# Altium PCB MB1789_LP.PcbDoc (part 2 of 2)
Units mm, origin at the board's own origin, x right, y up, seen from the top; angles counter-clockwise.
Board outline 60 x 34 mm, 4 copper layers (Top Layer, Mid-Layer 1, Mid-Layer 2, Bottom Layer), stack 1.07 mm thick; 67 components, 56 nets, 214 pads, 993 vias.

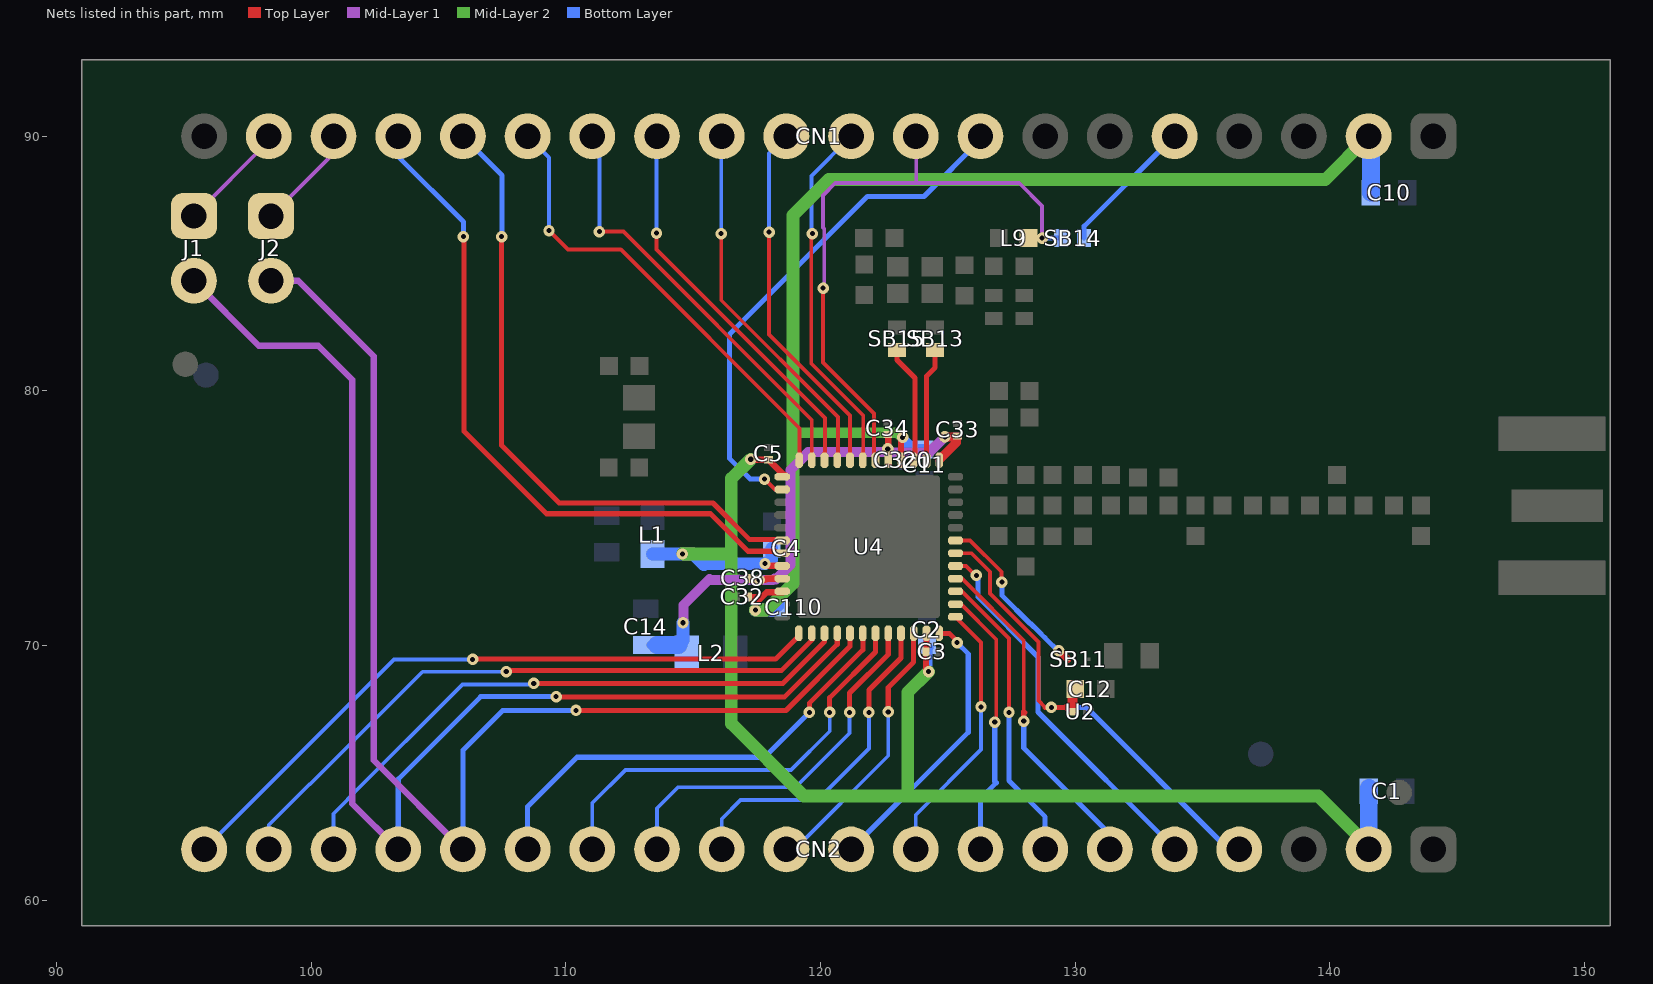
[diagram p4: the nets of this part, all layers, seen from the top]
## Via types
v1: diameter 0.45, hole 0.2, Top Layer to Bottom Layer, 992 vias
v2: diameter 0.45, hole 0.2, Top Layer to Bottom Layer, tented bottom, 1 vias

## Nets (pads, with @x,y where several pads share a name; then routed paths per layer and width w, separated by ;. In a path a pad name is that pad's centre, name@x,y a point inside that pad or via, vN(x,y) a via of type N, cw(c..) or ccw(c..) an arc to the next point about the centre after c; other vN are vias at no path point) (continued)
NetSB11_2: SB11.2 U4.19 | length 7
  Top Layer w0.15: U4.19@125.296,74.132 125.871,74.132 127.1,72.903 127.1,72.48 v1@127.12,72.46
  Top Layer w0.2: v1(129.36,69.8) v1@129.369,69.8
  Top Layer w0.3: v1@129.369,69.8 SB11.2@129.7,69.469
  Bottom Layer w0.2: v1(127.12,72.5) 127.12,71.98 128.224,70.875 128.245,70.875 128.555,70.565 ; 128.555,70.564 128.804,70.315 ; 128.805,70.315 129.36,69.76 v1(129.36,69.8)
NetSB13_1: SB13.1 U4.26 | length 4.5
  Top Layer w0.2: U4.26@124.158,77.282 124.158,80.578 124.5,80.92 SB13.1@124.5,81.6
NetSB15_1: SB15.1 U4.27 | length 4.6
  Top Layer w0.2: SB15.1@123,81.6 123,81.22 123.71,80.51 123.71,77.334 U4.27@123.658,77.282
NRST: C12.1 CN2.4 U2.1 U4.18 | length 19.5
  Top Layer w0.15: U4.18@125.296,73.632 125.926,73.632 126.655,72.903 126.655,72.05 128.555,70.15 128.555,67.845 128.82,67.58
  Top Layer w0.2: 128.82,67.58 v1(129.06,67.58) 129.588,67.58 129.608,67.6 129.648,67.56 129.688,67.6 U2.1@129.788,67.5 ; C12.1@129.888,68.188 C12.1@130,68.3
  Top Layer w0.4: U2.1@129.888,67.5 C12.1@129.888,68.188
  Bottom Layer w0.2: v1(129.06,67.58) 130.44,67.58 136.02,62 CN2.4@136.44,62
PA0: CN2.14 U4.7 | length 16.9
  Top Layer w0.2: v1(120.36,67.38) 120.36,67.957 122.158,69.755 U4.7@122.158,70.485
  Bottom Layer w0.15: CN2.14@111.04,62 111.04,63.82 112.34,65.12 118.84,65.12 120.36,66.64 v1(120.36,67.38)
PA1: CN2.13 U4.8 | length 15
  Top Layer w0.2: v1(121.14,67.38) 121.14,68.14 122.658,69.658 U4.8@122.658,70.485
  Bottom Layer w0.15: CN2.13@113.58,62 113.58,63.62 114.4,64.44 119.02,64.44 121.14,66.56 v1(121.14,67.38)
PA2: CN2.12 U4.9 | length 13.2
  Top Layer w0.2: v1(121.9,67.38) 121.9,68.26 123.158,69.518 U4.9@123.158,70.485
  Bottom Layer w0.15: CN2.12@116.12,62 116.12,63.2 116.86,63.94 119.88,63.94 121.9,65.96 v1(121.9,67.38)
PA3: CN2.11 U4.10 | length 10.8
  Top Layer w0.2: v1@122.6,67.36 122.66,67.42 122.66,68.36 123.658,69.358 U4.10@123.658,70.485
  Bottom Layer w0.15: CN2.11@118.66,62 118.98,62 122.66,65.68 v1(122.66,67.4)
PA4: CN2.10 U4.12 | length 11.1
  Top Layer w0.2: U4.12@124.658,70.485 125.055,70.485 125.4,70.14 v1@125.4,70.1
  Bottom Layer w0.2: CN2.10@121.2,62 125.8,66.6 125.8,69.68 v1(125.36,70.12)
PA5: CN2.9 U4.13 | length 10.6
  Top Layer w0.15: U4.13@125.296,71.132 126.3,70.128 v1(126.3,67.6)
  Bottom Layer w0.15: CN2.9@123.74,62 123.74,63.36 126.3,65.92 v1(126.3,67.6)
PA6: CN2.8 U4.14 | length 10.7
  Top Layer w0.15: U4.14@125.296,71.632 125.51,71.632 126.9,70.242 126.9,67.06 v1(126.84,67)
  Bottom Layer w0.2: CN2.8@126.28,62 126.28,64 126.9,64.62 126.84,64.68 v1(126.84,67)
PA7: CN2.7 U4.15 | length 11.7
  Top Layer w0.15: U4.15@125.296,72.132 125.548,72.132 127.4,70.28 v1(127.4,67.38)
  Bottom Layer w0.2: v1(127.4,67.38) 127.4,64.7 128.82,63.28 CN2.7@128.82,62
PA8: CN2.6 U4.16 | length 13.3
  Top Layer w0.15: U4.16@125.296,72.632 125.554,72.632 127.98,70.205 127.98,67.42
  Top Layer w0.2: v1(127.98,67.04) 127.98,67.34 128.02,67.38 127.98,67.42
  Bottom Layer w0.2: v1(127.98,67.04) 127.98,65.98 131.36,62.6 CN2.6@131.36,62
PA9: CN2.5 U4.17 | length 15
  Top Layer w0.15: U4.17@125.296,73.132 125.709,73.132 126.141,72.7 126.161,72.72 v1(126.121,72.76)
  Bottom Layer w0.2: v1@126.18,72.7 126.18,71.92 128.54,69.56 128.54,67.4 CN2.5@133.95,61.99
PA10: CN1.12 U4.33 | length 14.9
  Top Layer w0.15: v1@116.1,86.22 v1(116.1,86.18) 116.1,83.56 120.68,78.98 U4.33@120.68,77.26 ; U4.33@120.658,77.282 U4.33@120.658,77.541
  Bottom Layer w0.15: v1(116.1,86.18) 116.1,89.98 CN1.12@116.12,90
PA11: CN1.13 U4.34 | length 15.9
  Top Layer w0.15: v1@113.56,86.26 v1(113.56,86.2) 113.56,85.56 120.18,78.94 U4.34@120.18,77.3 ; U4.34@120.14,77.2 U4.34@120.14,77.54
  Bottom Layer w0.15: v1(113.56,86.2) 113.56,89.98 CN1.13@113.58,90
PA12: CN1.14 U4.35 | length 16.8
  Top Layer w0.15: v1(111.32,86.26) 112.26,86.26 119.658,78.862 U4.35@119.658,77.282
  Bottom Layer w0.15: CN1.14@111.04,90 111.32,89.72 v1(111.32,86.26)
PA13: CN1.15 U4.36 | length 18.3
  Top Layer w0.15: v1(109.34,86.3) 110.08,85.56 112.16,85.56 119.18,78.54 U4.36@119.18,77.3
  Bottom Layer w0.15: CN1.15@108.5,90 109.34,89.16 v1(109.34,86.3)
PA14: CN1.16 U4.42 | length 25.4
  Top Layer w0.2: v1@107.48,86.04 107.48,77.86 109.74,75.6 115.78,75.6 117.218,74.162 U4.42@118.6,74.162
  Bottom Layer w0.2: CN1.16@105.96,90 107.5,88.46 107.5,86.08 v1(107.48,86.06)
PA15: CN1.17 U4.43 | length 27.2
  Top Layer w0.2: v1@106,86.06 106,78.42 109.24,75.18 115.68,75.18 117.15,73.71 118.21,73.71 118.28,73.64 118.578,73.64 U4.43@118.6,73.662
  Bottom Layer w0.2: CN1.17@103.42,90 103.42,89.2 105.98,86.64 v1(105.98,86.06)
PB0: CN1.9 L9.2 SB14.1 U4.30 | length 24.8
  Top Layer w0.15: v1(120.1,84.04) 120.08,84.04 120.1,84.02 120.1,81.12 122.1,79.12 122.1,77.34 U4.30@122.158,77.282
  Top Layer w0.2: L9.2@128.16,86 v1(128.7,86)
  Mid-Layer 1 w0.15: v1@120.1,84.08 120.145,84.125 120.145,86.373 120.1,86.418 120.1,87.68 120.58,88.16 127.8,88.16 128.7,87.26 v1(128.7,86) ; CN1.9@123.74,89.94 123.76,89.96 123.76,88.16
  Bottom Layer w0.2: v1(128.7,86) SB14.1@129.45,86
PB2: CN1.10 U4.31 | length 14.5
  Top Layer w0.15: v1(119.68,86.18) 119.635,86.135 119.635,81.085 121.68,79.04 U4.31@121.68,77.32 ; U4.31@121.658,77.282 U4.31@121.658,77.562
  Bottom Layer w0.15: v1(119.68,86.18) 119.64,86.22 119.64,88.44 CN1.10@121.2,90
PB3: CN2.20 U4.1 | length 26.9
  Top Layer w0.2: v1@106.36,69.48 118.24,69.48 119.151,70.391 U4.1@119.151,70.485
  Bottom Layer w0.15: CN2.20@95.8,62 103.26,69.46 v1(106.34,69.46)
PB4: CN2.19 U4.2 | length 25.5
  Top Layer w0.2: v1@107.66,69.02 118.46,69.02 119.658,70.218 U4.2@119.658,70.485
  Bottom Layer w0.15: CN2.19@98.34,62 98.34,62.96 99.94,64.56 99.96,64.56 104.38,68.98 v1(107.66,68.98)
PB5: CN2.18 U4.3 | length 23.8
  Top Layer w0.2: v1@108.78,68.52 118.52,68.52 120.158,70.158 U4.3@120.158,70.485
  Bottom Layer w0.15: CN2.18@100.88,62 100.88,63.4 101.44,63.96 101.44,63.98 105.94,68.48 108.7,68.48 v1(108.74,68.52)
PB6: CN2.17 J1.2 U4.4 | length 49.7
  Top Layer w0.2: v1@109.58,67.98 118.58,67.98 120.658,70.058 U4.4@120.658,70.485
  Mid-Layer 1 w0.25: J1.2@95.4,84.33 97.95,81.78 100.28,81.78 101.62,80.44 101.62,63.8 CN2.17@103.42,62
  Bottom Layer w0.2: CN2.17@103.42,62 103.42,64.76 106.66,68 v1(109.62,68)
PB7: CN2.16 J2.2 U4.5 | length 47.4
  Top Layer w0.2: v1(110.4,67.46) 118.64,67.46 121.158,69.978 U4.5@121.158,70.485
  Mid-Layer 1 w0.2: 102.46,67.48 102.48,67.46
  Mid-Layer 1 w0.25: J2.2@98.425,84.328 99.492,84.328 102.46,81.36 102.46,67.48 102.46,65.5 CN2.16@105.96,62
  Bottom Layer w0.2: CN2.16@105.96,62 105.96,65.9 107.52,67.46 v1(110.4,67.46)
PB8: CN2.15 U4.6 | length 18.7
  Top Layer w0.15: U4.6@121.618,70.445 U4.6@121.658,70.485 U4.6@121.658,70.235
  Top Layer w0.2: v1@119.56,67.34 v1(119.56,67.38) 119.56,67.74 121.66,69.84 U4.6@121.66,70.56
  Bottom Layer w0.2: CN2.15@108.5,62 108.5,63.68 110.44,65.62 117.8,65.62 v1(119.56,67.38)
PB12: CN1.11 U4.32 | length 14.3
  Top Layer w0.15: v1@117.98,86.26 117.98,82.22 121.158,79.042 U4.32@121.158,77.282
  Bottom Layer w0.15: v1(117.98,86.24) 117.98,89.32 CN1.11@118.66,90
PC13: CN1.8 U4.38 | length 20.5
  Top Layer w0.15: v1(117.8,76.54) 118.208,76.132 U4.38@118.498,76.132
  Bottom Layer w0.2: v1(117.8,76.54) 117.24,76.54 116.42,77.36 116.42,82.221 121.839,87.64 124.06,87.64 CN1.8@126.32,89.9
UART_RX: CN1.18 J2.1 | length 4.1
  Mid-Layer 1 w0.15: J2.1@98.425,86.868 100.88,89.323 CN1.18@100.88,90
UART_TX: CN1.19 J1.1 | length 4.3
  Mid-Layer 1 w0.15: J1.1@95.4,86.87 98.34,89.81 CN1.19@98.34,90
VDD: C1.2 C2.2 C3.2 C4.2 C5.2 CN2.2 L1.1 U4.11 U4.37 U4.44 | length 57.7
  Top Layer w0.25: v1(117.26,77.32) 117.28,77.3 C5.2@117.96,77.3 U4.37@118.598,76.662 ; v1(117.82,73.22) 117.908,73.132 U4.44@118.498,73.132 ; C3.2@124.14,69.76 124.14,69.08 v1(124.24,68.98) ; U4.11@124.158,70.485 C3.2@124.16,69.8
  Top Layer w0.3: U4.37@118.598,76.662 U4.37@118.6,76.662
  Mid-Layer 2 w0.5: v1@114.6,73.62 114.62,73.6 116.5,73.6 ; v1(117.26,77.32) 116.5,76.56 116.5,73.6 ; v1(124.24,68.98) 123.42,68.16 123.42,64.1 ; CN2.2@141.56,62.08 139.54,64.1 123.42,64.1 ; 116.5,73.6 116.5,66.94 119.34,64.1 123.42,64.1
  Bottom Layer w0.25: C2.2@124.18,70.02 C2.2@124.258,69.942
  Bottom Layer w0.3: v1(124.24,68.98) 124.24,69.84 124.26,69.86 124.24,69.88 124.28,69.92 C2.2@124.258,69.942
  Bottom Layer w0.5: L1.1@113.4,73.6 115,73.6 115.425,73.175 115.47,73.22 v1(117.82,73.22) 117.835,73.22 117.875,73.26 117.958,73.26 118.082,73.384 C4.2@118.082,73.82
  Bottom Layer w0.7: CN2.2@141.52,61.98 C1.2@141.52,64.42
  other v1: 114.58,73.6
VDD_TCXO_EXT: CN1.5 SB14.2 | length 5.1
  Bottom Layer w0.2: SB14.2@130.35,86 130.35,86.47 CN1.5@133.6,89.72
VDDPA: C14.1 C33.2 C34.2 C38.1 L2.1 U4.25 U4.29 U4.45 | length 22.8
  Top Layer w0.254: C38.1@117.26,72.62 117.3,72.58 v1(117.588,72.58) 117.82,72.58 117.872,72.632 U4.45@118.498,72.632 ; U4.29@122.658,77.282 C34.2@122.658,78.18
  Top Layer w0.3: U4.25@124.658,77.282 U4.25@124.718,77.342
  Top Layer w0.35: U4.25@124.718,77.342 124.718,77.358 125.34,77.98 C33.2@125.34,78.2 ; v1(124.88,78.2) C33.2@125.38,78.2
  Mid-Layer 1 w0.4: v1(114.6,70.9) 114.62,70.92 114.62,71.6 115.64,72.62 115.68,72.58 v1(117.588,72.58) 118.129,72.58 118.168,72.62 118.174,72.614 118.2,72.64 118.24,72.6 118.82,73.18 118.82,76.9 119.52,77.6 122.578,77.6 122.64,77.662 v1(122.64,77.726) 122.64,77.698 122.748,77.59 124.27,77.59 124.85,78.17 v1@124.91,78.17
  Bottom Layer w0.4: C14.1@113.363,70.026 C14.1@113.574,70.026 ; L2.1@114.423,70.026 L2.1@114.6,70.204 ; L2.1@114.6,70.071 v1(114.6,70.9)
  Bottom Layer w0.5: L2.1@114.6,70.204 v1(114.6,70.9)
  Bottom Layer w0.7: C14.1@113.574,70.026 L2.1@114.423,70.026
VDDRF: C10.1 C11.1 C32.2 C110.1 C320.2 CN1.2 U4.28 U4.46 | length 53
  Top Layer w0.2: v1(117.44,71.4) 117.44,71.66 ; U4.46@118.558,72.12 U4.46@118.6,72.162
  Top Layer w0.25: C32.2@117.24,71.92 117.26,71.9 117.68,71.9 ; U4.46@118.558,72.12 118.543,72.105 117.885,72.105 117.68,71.9 ; v1@123.12,78.18 123.14,78.16 123.158,78.178 U4.28@123.158,77.282 ; v1@123.16,78.18 v1(123.22,78.18) ; 117.68,71.9 117.44,71.66 117.68,71.9
  Mid-Layer 2 w0.4: 118.92,78.36 123.015,78.36 123.195,78.18 v1(123.22,78.18)
  Mid-Layer 2 w0.5: v1(117.44,71.4) 117.88,71.4 118.92,72.44 118.92,78.36 118.92,86.9 120.32,88.3 139.82,88.3 CN1.2@141.52,90
  Bottom Layer w0.25: C320.2@123.22,77.52 123.22,78.155 v1(123.22,78.18)
  Bottom Layer w0.4: v1@123.22,78.155 123.655,77.72 C11.1@124.1,77.72
  Bottom Layer w0.5: v1(117.44,71.4) 118.12,71.4 118.32,71.6 C110.1@118.342,71.6
  Bottom Layer w0.7: CN1.2@141.52,90 141.607,89.912 C10.1@141.607,87.78
pads on no net: CN1.3 CN1.7 CN2.3 Designator1.1 Designator2.1 Designator3.1 Designator4.1 U4.23
copper on no net: | length 2656.1
  Top Layer w0.025: 179.648,184.046 182.18,186.578 185.228,189.626 188.276,192.674 191.324,195.722 194.372,198.77 197.42,201.818 200.468,204.866 203.516,207.914 206.564,210.962 208.088,212.486 ; 179.648,185.57 180.656,186.578 183.704,189.626 186.752,192.674 189.8,195.722 192.848,198.77 195.896,201.818 198.944,204.866 201.992,207.914 205.04,210.962 208.088,214.01 ; 179.648,187.094 182.18,189.626 185.228,192.674 188.276,195.722 191.324,198.77 194.372,201.818 197.42,204.866 200.468,207.914 203.516,210.962 206.564,214.01 208.088,215.534 ; 179.648,188.618 180.656,189.626 183.704,192.674 186.752,195.722 189.8,198.77 192.848,201.818 195.896,204.866 198.944,207.914 201.992,210.962 205.04,214.01 208.088,217.058 ; 179.648,190.142 182.18,192.674 185.228,195.722 188.276,198.77 191.324,201.818 194.372,204.866 197.42,207.914 200.468,210.962 203.516,214.01 206.564,217.058 ; 179.648,191.666 180.656,192.674 183.704,195.722 186.752,198.77 189.8,201.818 192.848,204.866 195.896,207.914 198.944,210.962 201.992,214.01 205.04,217.058 ; 179.648,193.19 182.18,195.722 185.228,198.77 188.276,201.818 191.324,204.866 194.372,207.914 197.42,210.962 200.468,214.01 203.516,217.058 ; 179.648,194.714 180.656,195.722 183.704,198.77 186.752,201.818 189.8,204.866 192.848,207.914 195.896,210.962 198.944,214.01 201.992,217.058 ; 179.648,196.238 182.18,198.77 185.228,201.818 188.276,204.866 191.324,207.914 194.372,210.962 197.42,214.01 200.468,217.058 ; 179.648,197.762 180.656,198.77 183.704,201.818 186.752,204.866 189.8,207.914 192.848,210.962 195.896,214.01 198.944,217.058 ; 179.648,199.286 182.18,201.818 185.228,204.866 188.276,207.914 191.324,210.962 194.372,214.01 197.42,217.058 ; 179.648,200.81 180.656,201.818 183.704,204.866 186.752,207.914 189.8,210.962 192.848,214.01 195.896,217.058 ; 179.648,202.334 182.18,204.866 185.228,207.914 188.276,210.962 191.324,214.01 194.372,217.058 ; 179.648,203.858 180.656,204.866 183.704,207.914 186.752,210.962 189.8,214.01 192.848,217.058 ; 179.648,205.382 182.18,207.914 185.228,210.962 188.276,214.01 191.324,217.058 ; 179.648,206.906 180.656,207.914 183.704,210.962 186.752,214.01 189.8,217.058 ; 179.648,208.43 182.18,210.962 185.228,214.01 188.276,217.058 ; 179.648,209.954 180.656,210.962 183.704,214.01 186.752,217.058 ; 179.648,211.478 182.18,214.01 185.228,217.058 ; 179.648,213.002 180.656,214.01 183.704,217.058 ; 179.648,214.526 182.18,217.058 ; 179.648,216.05 180.656,217.058 ; 180.656,183.53 183.704,186.578 186.752,189.626 189.8,192.674 192.848,195.722 195.896,198.77 198.944,201.818 201.992,204.866 205.04,207.914 208.088,210.962 ; 182.18,183.53 185.228,186.578 188.276,189.626 191.324,192.674 194.372,195.722 197.42,198.77 200.468,201.818 203.516,204.866 206.564,207.914 208.088,209.438 ; 183.704,183.53 186.752,186.578 189.8,189.626 192.848,192.674 195.896,195.722 198.944,198.77 201.992,201.818 205.04,204.866 208.088,207.914 ; 185.228,183.53 188.276,186.578 191.324,189.626 194.372,192.674 197.42,195.722 200.468,198.77 203.516,201.818 206.564,204.866 208.088,206.39 ; 186.752,183.53 189.8,186.578 192.848,189.626 195.896,192.674 198.944,195.722 201.992,198.77 205.04,201.818 208.088,204.866 ; 188.276,183.53 191.324,186.578 194.372,189.626 197.42,192.674 200.468,195.722 203.516,198.77 206.564,201.818 208.088,203.342 ; 189.8,183.53 192.848,186.578 195.896,189.626 198.944,192.674 201.992,195.722 205.04,198.77 208.088,201.818 ; 191.324,183.53 194.372,186.578 197.42,189.626 200.468,192.674 203.516,195.722 206.564,198.77 208.088,200.294 ; 192.848,183.53 195.896,186.578 198.944,189.626 201.992,192.674 205.04,195.722 208.088,198.77 ; 194.372,183.53 197.42,186.578 200.468,189.626 203.516,192.674 206.564,195.722 208.088,197.246 ; 195.896,183.53 198.944,186.578 201.992,189.626 205.04,192.674 208.088,195.722 ; 197.42,183.53 200.468,186.578 203.516,189.626 206.564,192.674 208.088,194.198 ; 198.944,183.53 201.992,186.578 205.04,189.626 208.088,192.674 ; 200.468,183.53 203.516,186.578 206.564,189.626 208.088,191.15 ; 201.992,183.53 205.04,186.578 208.088,189.626 ; 203.516,183.53 206.564,186.578 208.088,188.102 ; 205.04,183.53 208.088,186.578 ; 206.564,183.53 208.088,185.054
  Top Layer w0.381: 91.532,186.578 101.944,186.578 125.56,186.578 148.667,186.578 165.173,186.578 179.648,186.578 208.088,186.578 ; 91.532,189.626 101.944,189.626 125.56,189.626 148.667,189.626 165.173,189.626 179.648,189.626 208.088,189.626 ; 91.532,192.674 101.944,192.674 125.56,192.674 148.667,192.674 165.173,192.674 179.648,192.674 208.088,192.674 ; 91.532,195.722 101.944,195.722 125.56,195.722 148.667,195.722 165.173,195.722 179.648,195.722 208.088,195.722 ; 91.532,198.77 101.944,198.77 125.56,198.77 148.667,198.77 165.173,198.77 179.648,198.77 208.088,198.77 ; 91.532,201.818 101.944,201.818 125.56,201.818 148.667,201.818 165.173,201.818 179.648,201.818 208.088,201.818 ; 91.532,204.866 101.944,204.866 125.56,204.866 148.667,204.866 165.173,204.866 179.648,204.866 208.088,204.866 ; 91.532,207.914 101.944,207.914 125.56,207.914 148.667,207.914 165.173,207.914 179.648,207.914 208.088,207.914 ; 91.532,210.962 101.944,210.962 125.56,210.962 148.667,210.962 165.173,210.962 179.648,210.962 208.088,210.962 ; 91.532,214.01 101.944,214.01 125.56,214.01 148.667,214.01 165.173,214.01 179.648,214.01 208.088,214.01 ; 91.532,217.058 208.088,217.058 ; 101.944,220.106 101.944,183.53 ; 125.56,220.106 125.56,183.53 ; 148.667,220.106 148.667,183.53 ; 165.173,220.106 165.173,183.53 ; 179.648,220.106 179.648,183.53 ; 101.944,183.53 125.56,183.53 ; 101.944,183.53 91.532,183.53 91.532,220.106 208.088,220.106 208.088,183.53 179.648,183.53 ; 125.56,183.53 148.667,183.53 ; 148.667,183.53 165.173,183.53 ; 165.173,183.53 179.648,183.53

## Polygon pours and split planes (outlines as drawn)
GND on Top Layer "GND_Top" (solid, remove dead copper, pour order 8): 91,92.92 91.06,92.98 150.76,92.98 150.76,59.02 91.06,59.02 91.06,92.98
GND on Mid-Layer 1 "GND_L02_P010" (solid, remove dead copper, pour order 10): 91.06,92.92 150.94,92.92 150.94,59.14 150.82,59.02 91,59.02 91,92.86 91.06,92.92
GND on Mid-Layer 2 "GND_L03_P012" (solid, remove dead copper, pour order 12): 91.08,93 150.76,93 150.76,59.14 150.82,59.08 150.76,59.02 91.08,59.02 91.08,93
GND on Bottom Layer "GND_L04_P014" (solid, remove dead copper, pour order 14): 91.08,93 150.82,93 150.82,59.14 150.7,59.02 91.02,59.02 91.02,93.12

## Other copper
Top Layer:
  region net NetC27_2: 125.8,75.5 126.7,76.4 126.7,77.02 125.62,75.78 125.48,75.78 125.48,75.52 125.5,75.5
  pour cut-out: 118.72,77.04 125.04,77.04 124.98,76.98 124.98,70.76 119.02,70.76 118.82,70.76 119.34,71.28 119.34,71.6 119.2,71.74 118.721,71.261
  region net NetC15_1: 125.1,76.7 125.1,77 126.3,78.2 127,78.2 127,77.6 126.4,77.6 125.5,76.7
  pour cut-out: 123.4,77.5 123.362,79.278 120.96,81.68 120.96,84.8 121.9,84.8 121.9,86.5 128.8,86.5 128.8,84.8 128.8,81.8 128.8,82 128.3,81.4 126.48,81.4 124.54,79.46 124.54,77.74 124.3,77.5
  region net NetC28_1: 146.144,75.799 147.069,76.135 147.125,76.135 147.125,74.865 147.097,74.865 146.144,75.198
  pour cut-out: 129.565,77.215 129.838,77.215 129.838,73.838 129.565,73.838
  pour cut-out: 126.7,76.3 130.7,76.3 130.772,76.228 130.772,75.972 126.705,75.972 126.695,75.961
  pour cut-out: 126.7,75.1 130.7,75.1 130.7,74.7 126.7,74.7
  pour cut-out: 130.64,76.3 132.1,76.3 132.1,75.9 130.64,75.9
  pour cut-out: 132.925,77.115 133.198,77.115 133.196,74.985 132.924,74.985
  pour cut-out: 127.424,74.006 127.49,73.94 129.95,73.94 129.95,73.44 128.29,73.44 127.521,73.44 127.424,73.538
  pour cut-out: 130.462,68.762 130.525,68.7 130.9,68.7 130.9,67.9 130.4,67.9
  pour cut-out: 122.1,86.4 122.6,86.4 122.6,85.5 122.5,85.6 122.1,85.6
  pour cut-out: 127.4,86.4 127.8,86.4 127.8,85.6 127.4,85.6
  pour cut-out: 127.2,85.3 127.7,85.3 127.7,84.6 127.6,84.5 127.2,84.5
  pour cut-out: 112.1,81.36 112.5,81.36 112.5,80.56 112.2,80.56 112.1,80.66
  pour cut-out: 112.12,77.4 112.52,77.4 112.52,76.6 112.42,76.7 112.12,76.7
  pour cut-out: 112.12,79.2 113.52,79.2 113.52,78.7 112.12,78.7
  pour cut-out: 127.4,80.462 127.7,80.462 127.7,77.2 127.4,77.2
  region net GND: 124.7,84.2 126.4,84.2 126.6,84 126.6,83.4 126.1,83.4 126.1,83 125.4,83 124.9,83.5 124.7,83.5
  pour cut-out: 125.6,77.4 127.54,77.4 127.54,71.52 125.6,73.46
  pour cut-out: 125.1,78.74 125.68,78.74 125.7,78.72 125.7,78.48 125.12,78.48 125.1,78.5 125.12,78.52 125.12,78.72
  pour cut-out: 124.26,69.42 124.26,70 124.28,70.02 124.52,70.02 124.52,69.44 124.5,69.42 124.48,69.44 124.28,69.44
  pour cut-out: 116.82,71.58 116.84,72.94 117.08,72.94 117.08,71.6 117.06,71.58 117.04,71.6 116.84,71.6
  pour cut-out: 118.26,77.42 117.68,77.42 117.66,77.44 117.66,77.68 118.24,77.68 118.26,77.66 118.24,77.64 118.24,77.44
  pour cut-out: 122.96,78.36 122.38,78.36 122.36,78.38 122.36,78.62 122.94,78.62 122.96,78.6 122.94,78.58 122.94,78.38
  text "Layer" at 93.31,217.82 h1.52
  text "Name" at 103.722,217.82 h1.52
  text "Material" at 127.338,217.82 h1.52
  text "Thickness" at 150.445,217.82 h1.52
  text "Constant" at 166.951,217.82 h1.52
  text "Board Layer Stack" at 181.426,217.82 h1.52
  text "Top Overlay" at 103.722,214.772 h1.52
  text "Top Solder" at 103.722,211.724 h1.52
  text "Solder Resist" at 127.338,211.724 h1.52
  text "0.79mil" at 150.445,211.724 h1.52
  text "3.7" at 166.951,211.724 h1.52
  text "1" at 93.31,208.676 h1.52
  text "Top Layer" at 103.722,208.676 h1.52
  text "Copper" at 127.338,208.676 h1.52
  text "1.38mil" at 150.445,208.676 h1.52
  text "Dielectric 1" at 103.722,205.628 h1.52
  text "1x106 + 1x2116" at 127.338,205.628 h1.52
  text "6.30mil" at 150.445,205.628 h1.52
  text "3.7" at 166.951,205.628 h1.52
  text "2" at 93.31,202.58 h1.52
  text "Mid-Layer 1" at 103.722,202.58 h1.52
  text "Copper" at 127.338,202.58 h1.52
  text "1.38mil" at 150.445,202.58 h1.52
  text "Dielectric2" at 103.722,199.532 h1.52
  text "FR-4" at 127.338,199.532 h1.52
  text "24.02mil" at 150.445,199.532 h1.52
  text "5" at 166.951,199.532 h1.52
  text "3" at 93.31,196.484 h1.52
  text "Mid-Layer 2" at 103.722,196.484 h1.52
  text "Copper" at 127.338,196.484 h1.52
  text "1.38mil" at 150.445,196.484 h1.52
  text "Dielectric3" at 103.722,193.436 h1.52
  text "1x106 + 1x2116" at 127.338,193.436 h1.52
  text "6.30mil" at 150.445,193.436 h1.52
  text "3.7" at 166.951,193.436 h1.52
  text "4" at 93.31,190.388 h1.52
  text "Bottom Layer" at 103.722,190.388 h1.52
  text "Copper" at 127.338,190.388 h1.52
  text "1.38mil" at 150.445,190.388 h1.52
  text "Bottom Solder" at 103.722,187.34 h1.52
  text "Solder Resist" at 127.338,187.34 h1.52
  text "0.79mil" at 150.445,187.34 h1.52
  text "3.7" at 166.951,187.34 h1.52
  text "Bottom Overlay" at 103.722,184.292 h1.52
Mid-Layer 1:
  pour cut-out: 146.18,76.4 146.18,74.6 131.14,74.6 131.14,73.8 130.94,73.4 126.84,73.4 125.64,74.6 125.64,76.9 126.34,77.6 134.54,77.6 134.84,77.3 134.84,76.6 135.04,76.4
  pour cut-out: 147.12,76.8 151,76.8 151,74.3 147.12,74.3
  pour cut-out: 146.21,76.4 147.11,76.8 147.11,74.3 146.21,74.6
  region net GND: 123.9,87.2 126.1,87.2 126.1,83 125.4,83 125.4,83.4 123.9,83.4
  pour cut-out: 123.4,77.5 123.4,79.229 120.96,81.669 120.96,84.8 121.9,84.8 121.9,86.5 128.8,86.5 128.8,84.8 128.8,81.8 128.8,82 128.3,81.4 126.44,81.4 124.56,79.52 124.56,77.76 124.3,77.5
Mid-Layer 2:
  region net GND: 124,84.2 125.7,84.2 125.7,83.2 125.4,83.5 124,83.5
  region net GND: 123.9,87.2 126.1,87.2 126.1,83 125.4,83 125.4,83.4 123.9,83.4
  pour cut-out: 123.4,77.5 123.4,79.24 120.96,81.68 120.96,84.8 121.9,84.8 121.9,86.5 128.8,86.5 128.8,84.8 128.8,81.8 128.8,82 128.3,81.4 126.48,81.4 124.54,79.46 124.54,77.74 124.3,77.5
Bottom Layer:
  pour cut-out: 123.66,70.88 124.709,70.88 124.72,70.891 124.72,70.34 123.64,70.34 123.614,70.366 123.614,70.9
  pour cut-out: 123.64,77.46 124.48,77.46 124.48,76.76 123.64,76.76
  region net GND: 123.9,87.2 126.1,87.2 126.1,83 125.4,83 125.4,83.4 123.9,83.4
  pour cut-out: 115.3,70.4 116.1,70.4 116.1,69 115.3,69
  pour cut-out: 123.4,77.5 123.4,79.229 120.96,81.669 120.96,84.8 121.9,84.8 121.9,86.5 128.8,86.5 128.8,84.8 128.8,81.8 128.8,82 128.3,81.4 126.46,81.4 124.56,79.5 124.56,77.76 124.3,77.5

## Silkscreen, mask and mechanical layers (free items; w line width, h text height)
Top Overlay:
  rectangle: 93.42,68.36 100.84,74.9
  lines w0.15: 94.902,91.984 96.209,91.984 ; 95.055,92.322 96.055,92.322 ; 95.305,92.66 95.805,92.66 ; 95.551,90.972 95.551,91.982 ; 130.706,92.029 132.013,92.029 ; 130.86,92.367 131.86,92.367 ; 131.11,92.704 131.61,92.704 ; 131.355,91.016 131.355,92.027 ; 135.784,92.035 137.091,92.035 ; 135.938,92.373 136.938,92.373 ; 136.188,92.711 136.688,92.711 ; 136.433,91.023 136.433,92.033 ; 143.416,92.046 144.722,92.046 ; 143.429,64.028 144.736,64.028 ; 143.569,92.384 144.569,92.384 ; 143.583,64.366 144.583,64.366 ; 143.819,92.722 144.319,92.722 ; 143.833,64.703 144.333,64.703 ; 144.064,91.034 144.064,92.044 ; 144.078,63.015 144.078,64.026
  text "U_TX" at 96.98,91.272 h1
  text "U_RX" at 99.56,91.272 h1
  text "PA15" at 102.158,91.105 h1
  text "PA13" at 107.529,91.105 h1
  text "PA10" at 115.451,91.105 h1
  text "PB0" at 122.992,91.105 h1
  text "PC13" at 125.176,91.105 h1
  text "N/C" at 128.1,91.105 h1
  text "PB0" at 133.22,91.105 h1
  text "N/C" at 138.26,91.105 h1
  text "PA14" at 104.847,91.094 h1
  text "PA12" at 110.213,91.094 h1
  text "PA11" at 112.891,91.094 h1
  text "PB12" at 118.133,91.094 h1
  text "PB2" at 120.811,91.094 h1
  text "VDDRF" at 140.061,91.094 h1
  text "UART_TX" at 92.6,88.3 h1.5 r270
  text "UART_RX" at 100.5,88.1 h1.5 r270
  text "MB1789" at 93.62,77.56 h2
  text "LP Mode - 4L" at 93.76,75.7 h1.23
  text "PB3" at 94.8,60.225 h1
  text "PB4" at 97.359,60.228 h1
  text "PB5" at 99.916,60.228 h1
  text "PB6" at 102.48,60.226 h1
  text "PB7" at 105.039,60.228 h1
  text "PB8" at 107.598,60.226 h1
  text "PA0" at 110.159,60.226 h1
  text "PA1" at 112.716,60.226 h1
  text "PA2" at 115.151,60.226 h1
  text "PA3" at 117.704,60.225 h1
  text "PA4" at 120.263,60.228 h1
  text "PA5" at 122.82,60.228 h1
  text "PA6" at 125.384,60.226 h1
  text "PA7" at 127.943,60.228 h1
  text "PA8" at 130.502,60.226 h1
  text "PA9" at 133.063,60.226 h1
  text "NRST" at 135.13,60.217 h1
  text "N/C" at 138.26,60.216 h1
  text "VDD" at 140.583,60.228 h1
Top Paste:
  lines w0.5: 104.34,85.52 cw(c106.19,85.52) 106.19,87.37 ; 104.349,67.953 104.349,85.453 ; 104.36,68.02 ccw(c106.21,68.02) 106.21,66.17 ; 106.18,66.14 143.08,66.14 ; 106.18,87.38 143.08,87.38 ; 143.09,87.39 cw(c143.09,85.54) 144.94,85.54 ; 143.13,66.15 ccw(c143.13,68) 144.98,68 ; 144.94,78.74 144.94,85.49 ; 144.96,68.02 144.96,72.56
Top Solder:
  rectangle: 127.66,77.48 128.4,78.2
  rectangle: 128.74,72.72 129.48,73.44
  lines w1.5: 144.924,85.306 145,85.23 145,79.38 145.98,78.4 150.14,78.4 ; 144.947,67.964 144.947,71.847 145.7,72.6 150.04,72.6 ; 144.949,68.013 cw(c143.099,68.013) 143.099,66.163 106.199,66.163 cw(c106.199,68.013) 104.349,68.013 104.349,85.513 cw(c106.199,85.513) 106.199,87.363 143.099,87.363 cw(c143.099,85.513) 144.949,85.513
Bottom Solder:
  region: 111.3,72.1 117.52,72.1 117.54,72.12 117.68,71.98 117.68,67.5 111.42,67.5 111.34,67.42 111.34,72.06
Mechanical 1:
  lines w0.3: 150.98,59 91,59 91,93 151,93 151,59
Top Assembly (Mech14):
  lines w0.1: 91.045,59.048 150.949,59.048 150.949,92.949 91.045,92.949 91.045,59.048
Bottom Assembly (Mech15):
  lines w0.1: 91.044,59.047 150.948,59.047 150.948,92.948 91.044,92.948 91.044,59.047
Drill Drawing:
  lines w0.254: 92.802,171.993 94.496,171.993 93.649,170.299 92.802,171.993 ; 92.802,174.109 94.496,174.109 94.496,175.803 92.802,175.803 92.802,174.109
  lines w0.381: 91.284,169.156 292.295,169.156 ; 91.284,176.776 292.295,176.776 ; 105.276,165.346 105.276,180.586 ; 121.781,165.346 121.781,180.586 ; 149.459,165.346 149.459,180.586 ; 162.308,165.346 162.308,180.586 ; 180.947,165.346 180.947,180.586 ; 219.036,165.346 219.036,180.586 ; 234.018,165.346 234.018,180.586 ; 252.961,165.346 252.961,180.586 ; 269.467,165.346 269.467,180.586 ; 91.284,165.346 292.295,165.346 292.295,180.586 91.284,180.586 91.284,165.346
  text "Symbol" at 93.57,177.919 h1.83
  text "Count" at 106.419,177.919 h1.83
  text "Hole Size" at 122.924,177.919 h1.83
  text "Plated" at 150.602,177.919 h1.83
  text "Hole Type" at 163.451,177.919 h1.83
  text "Drill Layer Pair" at 182.09,177.919 h1.83
  text "Via/Pad" at 220.179,177.919 h1.83
  text "Pad Shape" at 235.161,177.919 h1.83
  text "Template" at 254.104,177.919 h1.83
  text "Description" at 270.61,177.919 h1.83
  text "44" at 106.419,174.109 h1.52
  text "1.000mm (39.37mil)" at 122.924,174.109 h1.52
  text "PTH" at 150.602,174.109 h1.52
  text "Round" at 163.451,174.109 h1.52
  text "Top Layer - Bottom Layer" at 182.09,174.109 h1.52
  text "Pad" at 220.179,174.109 h1.52
  text "(Mixed)" at 235.161,174.109 h1.52
  text "(Mixed)" at 254.104,174.109 h1.52
  text "993" at 106.419,170.299 h1.52
  text "0.200mm (7.87mil)" at 122.924,170.299 h1.52
  text "PTH" at 150.602,170.299 h1.52
  text "Round" at 163.451,170.299 h1.52
  text "Top Layer - Bottom Layer" at 182.09,170.299 h1.52
  text "Via" at 220.179,170.299 h1.52
  text "Rounded" at 235.161,170.299 h1.52
  text "(Mixed)" at 254.104,170.299 h1.52
  text "1037 Total" at 106.419,166.489 h1.52
  text "mils" at 114.86,150.273 h2.54
  text "mils" at 125.914,150.273 h2.54

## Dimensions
90.96,93.016 to 90.98,58.974 on Bottom Assembly
150.971,59.077 to 90.96,58.922 on Bottom Assembly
